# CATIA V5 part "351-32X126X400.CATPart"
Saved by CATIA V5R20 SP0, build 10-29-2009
Part number: 351-32X126X400
Definition: NONE
Nomenclature: 351-32X126X400
Source: Unknown
Description: 351-32X126X400
Bounding box of the stored display mesh (mm): x -7 to 393, y -22.5 to 22.5, z -22.5 to 22.5
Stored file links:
  C:\Users\Utente\Desktop\IO LAVORO\3D X SITO CF\X SITO\PLASTICA\351\351-32X126X400.CATPart

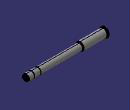
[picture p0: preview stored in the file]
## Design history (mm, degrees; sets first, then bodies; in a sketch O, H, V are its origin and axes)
Body1 "351-32X126X400" (main body)
  Solid1: solid without history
